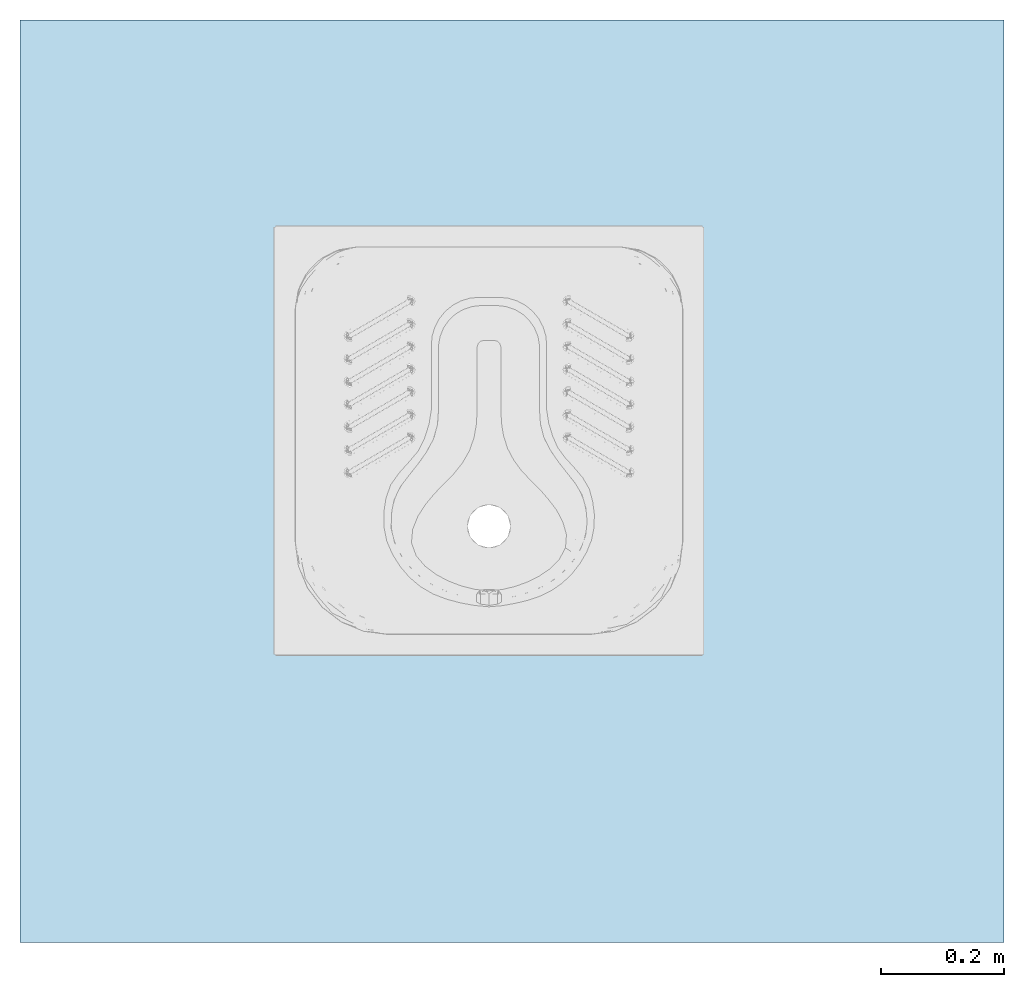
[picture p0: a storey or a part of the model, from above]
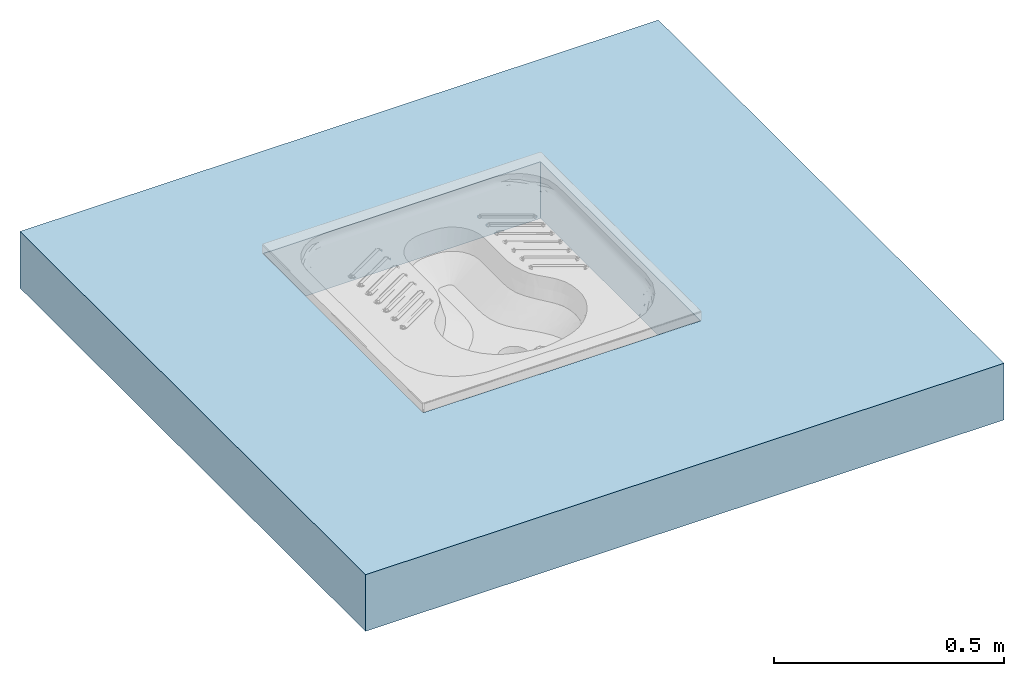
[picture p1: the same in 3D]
Properties of the parts of a building model (IFC2X3)

# File
Description: ViewDefinition [CoordinationView]
File name: Project Number
Time: 2017-01-31T15:07:55
Written by: Autodesk Revit Architecture 2011 - 1.0
Made in: 20100326_1700(x64)

# IfcProject, Project Number
Phase: Project Status

# IfcSite, Default
RefLatitude: 42, 21, 30, 344238; RefLongitude: -71, -3, -35, -194702; RefElevation: 0 mm

# IfcBuilding
Pset_BuildingCommon - NumberOfStoreys: 1
PSet_Revit_Other - Project Issue Date: Issue Date; Project Status: Project Status; Client Name: Owner; Project Address: Enter address here; Project Name: Project Name; Project Number: Project Number

# IfcBuildingStorey, Level 1
Elevation: 0 mm
PSet_Revit_Identity Data - Name: Level 1
PSet_Revit_Constraints - Elevation: 0 mm
PSet_Revit_Type_Graphics - Line Weight: 1; Color: 0; Line Pattern: Centre; Symbol: M_Level Head - Circle; Symbol at End 1 Default: no; Symbol at End 2 Default: yes
PSet_Revit_Type_Constraints - Elevation Base: 0
PSet_Revit_Type_Dimensions - Automatic Room Computation Height: no; Computation Height: 1200 mm

# IfcBuildingElementProxy: 113610, 113610:113610:113610:184529
In: Level 1
PSet_Revit_Constraints - Level: Level 1
PSet_Revit_Mechanical - System Type: Domestic Cold Water,Sanitary; System Name: Default Domestic Cold Water (Polantis_Production),Default Sanitary (Polantis_Production)
PSet_Revit_Identity Data - Mark: 16
PSet_Revit_Phasing - Phase Created: New Construction
PSet_Revit_Type_Data - Weight: 6kg
PSet_Revit_Type_Other - WarrantyDurationUnit: 10 years; WarrantyDescription: Any manufacturing defect; SerialNumber: 3456330163637; NominalWidth: 700 mm; NominalLength: 700 mm; NominalHeight: 30 mm; Name: SHA 700 squat WC pan; ModelNumber: 113610; Material: 304 stainless steel; Grade: CE; Finish: Polished satin; Features: Floor-recessed squat WC pan. Bacteriostatic 304 stainless steel. Stainless steel thickness 1.2mm. One-piece pressed WC bowl, seam-free for easy maintenance and better hygiene. Bowl shape suitable for male and female use. Non-slip foot area. Vertical waste outlet: Ø 100mm. Flushing system with one 304 stainless steel spreader. Weight: 6kg.
PSet_Revit_Type_General - Version: v1; ProductInformation: http://www.delabie.com/products/113610; ManufacturerURL: http://www.delabie.com/; ManufacturerName: DELABIE; Category: WC
PSet_Revit_Type_Identity Data - URL: http://www.delabie.com/; Type Comments: Recessed squat WC pan; Model: SHA 700 squat WC pan; Manufacturer: DELABIE; Description: French manufacturer Delabie is a leader in the European sanitary ware market for non-domestic places. Water controls, solutions for disabled people, sanitary ware, for schools, leisure centres, offices, hospitals, airports…
PSet_Revit_Type_Dimensions - Radius (Out): 25 mm; Radius (In): 7.7 mm

# IfcOpeningElement: Opening
In: Level 1
Pset_SlabCommon - Reference: Floor:Generic 150mm; IsExternal: no; LoadBearing: yes
PSet_Revit_Constraints - Level: Level 1; Height Offset From Level: 0 mm; Room Bounding: yes; Related to Mass: no
PSet_Revit_Structural - Structural: no
PSet_Revit_Phasing - Phase Created: New Construction
PSet_Revit_Dimensions - Perimeter: 6200 mm; Area: 1916975 mm2; Volume: 287546246 mm3; Thickness: 150 mm
PSet_Revit_Analytical Model - Vertical Projection: Default
PSet_Revit_Structural Analysis - Structural Usage: 3
PSet_Revit_Type_Construction - Default Thickness: 150 mm; Function: 0
PSet_Revit_Type_Graphics - Coarse Scale Fill Color: 0

# IfcSlab: Floor:Generic 150mm, Floor:Generic 150mm:182125
In: Level 1
PredefinedType: FLOOR; Material: Default Floor 150 mm
Pset_SlabCommon - Reference: Floor:Generic 150mm; IsExternal: no; LoadBearing: yes
PSet_Revit_Constraints - Level: Level 1; Height Offset From Level: 0 mm; Room Bounding: yes; Related to Mass: no
PSet_Revit_Structural - Structural: no
PSet_Revit_Phasing - Phase Created: New Construction
PSet_Revit_Dimensions - Perimeter: 6200 mm; Area: 1916975 mm2; Volume: 287546246 mm3; Thickness: 150 mm
PSet_Revit_Analytical Model - Vertical Projection: Default
PSet_Revit_Structural Analysis - Structural Usage: 3
PSet_Revit_Type_Construction - Default Thickness: 150 mm; Function: 0
PSet_Revit_Type_Graphics - Coarse Scale Fill Color: 0
